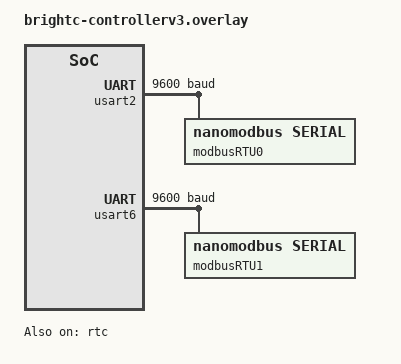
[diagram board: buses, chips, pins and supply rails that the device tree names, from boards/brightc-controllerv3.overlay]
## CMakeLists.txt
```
#-------------------------------------------------------------------------------
# Zephyr Example Application
#
# Copyright (c) 2021 Nordic Semiconductor ASA
# SPDX-License-Identifier: Apache-2.0

cmake_minimum_required(VERSION 3.13.1)
find_package(Zephyr REQUIRED HINTS $ENV{ZEPHYR_BASE})

project(app LANGUAGES C)

target_sources(app PRIVATE
    src/main.c
    src/application/active_objects/ao_modbus.c
    src/application/active_objects/ao_network.c
    src/application/active_objects/ao_sensor_matrix.c
    src/application/zbus/network_channels.c
    src/application/modbus/modbus_registry.c
    src/application/modbus/modbus_device_table.c
    src/domain/services/cwt_tm16pt_codec.c
    src/domain/services/jsy_mk339_codec.c
    src/domain/services/mbsl32di_codec.c
    src/domain/services/sensor_matrix_mapper.c
    src/domain/services/thermodynamic_engine.c
    src/domain/services/slave_scheduler.c
    src/domain/services/waveshare_relay_codec.c
    src/application/active_objects/ao_storage.c
    src/application/active_objects/ao_system_indicator.c
    src/application/active_objects/ao_digital_input.c
    src/application/zbus/config_channels.c
    src/application/zbus/indicator_channels.c
    src/application/zbus/digital_input_channels.c
    src/domain/services/digital_input_aggregator.c
    src/infrastructure/adapters/adapter_led_gpio.c
    src/infrastructure/adapters/adapter_buzzer_pwm.c
    src/infrastructure/adapters/adapter_di_gpio.c
    src/infrastructure/adapters/adapter_relay_gpio.c
    src/infrastructure/adapters/adapter_sensor_zephyr.c
    src/infrastructure/di/composition_root.c
    src/domain/models/hvac_unit_entity.c
    src/domain/models/hvac_group_entity.c
    src/application/zbus/hvac_channels.c
    src/application/zbus/sensor_channels.c
    src/infrastructure/adapters/adapter_hvac_actuator.c
    src/application/active_objects/ao_hvac.c
    src/application/services/app_facade.c
    src/domain/alarm/alarm_entity.c
    src/domain/alarm/alarm_aggregate.c
    src/domain/alarm/alarm_evaluator.c
    src/domain/alarm/alarm_registry.c
    src/application/zbus/alarm_channels.c
    src/application/active_objects/ao_alarm_manager.c
    src/infrastructure/adapters/adapter_alarm_detector_di.c
    src/infrastructure/adapters/adapter_alarm_detector_temp.c
    src/infrastructure/adapters/adapter_alarm_detector_volt.c
    src/infrastructure/adapters/adapter_alarm_detector_hvac.c
    src/domain/thermal_energy/humidity_transducer.c
    src/domain/thermal_energy/psychrometrics.c
    src/domain/thermal_energy/thermodynamics.c
    src/domain/thermal_energy/compressor_fsm.c
    src/domain/thermal_energy/predictive_analytics.c
    src/infrastructure/adapters/sensor_matrix_mapper.c
    src/application/zbus/thermal_channels.c
    src/application/active_objects/ao_thermal_energy.c
    src/domain/time/rtc_time_calc.c
    src/infrastructure/adapters/adapter_rtc_zephyr.c
    src/domain/storage/sd_lifecycle_sm.c
    src/application/zbus/storage_channels.c
    src/application/active_objects/ao_storage_sd.c
    src/infrastructure/adapters/adapter_storage_sd_zephyr.c
    src/infrastructure/adapters/adapter_modbus_tcp_server.c
    src/application/active_objects/ao_modbus_tcp.c
    src/domain/storage/bkpsram_ring.c
    src/infrastructure/adapters/adapter_bkpsram_stm32.c
    src/application/active_objects/ao_datalogger.c
    src/application/zbus/system_channels.c
)

if(CONFIG_SHELL)
    target_sources(app PRIVATE
        src/presentation/shell/shell_brightc.c
    )
endif()

if(CONFIG_MICROCONF)
    target_sources(app PRIVATE
        src/infrastructure/adapters/adapter_storage_microconf.c
    )
endif()

if(CONFIG_NETWORKING)
    target_sources(app PRIVATE
        src/infrastructure/adapters/adapter_eth_stm32.c
        src/infrastructure/adapters/adapter_wifi_esp_hosted.c
    )
endif()

target_include_directories(app PRIVATE
    include
    src
    lib
    # Public API of the out-of-tree ADC DMA engine. The header is always on the
    # include path so the composition root can reference the port-agnostic
    # adapter type even on platforms where the driver is not built.
    ${CMAKE_CURRENT_SOURCE_DIR}/../drivers/adc_dma/include
)

# The nanoMODBUS transport adapter is the only part that depends on the stack,
# so it is only compiled when the stack is enabled.
if(CONFIG_NANOMODBUS)
    target_sources(app PRIVATE
        src/infrastructure/adapters/adapter_modbus_nmbs.c
        src/infrastructure/adapters/adapter_relay_modbus.c
    )
endif()

# Bring-up diagnostic for a silent Modbus slave. Off unless the build asks for
# it, so a normal image carries no probe code at all.
if(CONFIG_APP_MODBUS_BUS_PROBE)
    target_sources(app PRIVATE src/application/diagnostics/modbus_bus_probe.c)
endif()

# The code below locates the git index file for this repository and adds it as a dependency for
# the application VERSION file so that if the repo has a new commit added, even if no files in
# the build have changed, the application version file will be regenerated with the new git commit
find_package(Git QUIET)
if(GIT_FOUND)
  execute_process(
    COMMAND ${GIT_EXECUTABLE} rev-parse --absolute-git-dir
    WORKING_DIRECTORY .
    OUTPUT_VARIABLE application_git_dir
    OUTPUT_STRIP_TRAILING_WHITESPACE
    ERROR_STRIP_TRAILING_WHITESPACE
    ERROR_VARIABLE stderr
    RESULT_VARIABLE return_code
  )
  # If there is an error e.g. it is not a git repo, we just silently ignore it and continue
  # without a dependency, this will be the case with freestanding applications.
  if(NOT return_code)
    if(NOT "${stderr}" STREQUAL "")
      message(WARNING "Application build version git rev-parse warned: ${stderr}")
    endif()

    set_property(TARGET app_version_h PROPERTY APP_VERSION_DEPENDS ${application_git_dir}/index)
  endif()
endif()
```

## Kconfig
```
# Copyright (c) 2021 Nordic Semiconductor ASA
# SPDX-License-Identifier: Apache-2.0
#
# This file is the application Kconfig entry point. All application Kconfig
# options can be defined here or included via other application Kconfig files.
# You can browse these options using the west targets menuconfig (terminal) or
# guiconfig (GUI).

menu "Zephyr"
source "Kconfig.zephyr"
endmenu

module = APP
module-str = APP
source "subsys/logging/Kconfig.template.log_config"

config APP_MODBUS_BUS_PROBE
	bool "Modbus bring-up diagnostic"
	depends on NANOMODBUS
	default n
	help
	  Sweep the Modbus slave addresses and the energy-meter register window
	  once at boot, before the polling threads claim the bus, and log every
	  outcome. It separates an addressing problem from a register-map one on
	  a slave that answers nothing. Diagnostic builds only: it costs one
	  transaction per probe and delays startup.

config APP_MODBUS_INTER_POLL_DELAY_MS
	int "Inter-poll turnaround delay in milliseconds"
	default 40
	range 0 1000
	help
	  Turnaround delay between consecutive Modbus transactions on the same
	  RS-485 bus. Gives slave transceivers time to release the bus and
	  satisfies the Modbus RTU inter-frame silence interval (t3.5+).

menu "BrightC Network Configuration"

config BRIGHTC_WIFI_DEFAULT_SSID
	string "Default Wi-Fi Soft-AP SSID"
	default "BrightC-AP"
	help
	  Default SSID broadcasted by the soft-AP interface.

config BRIGHTC_WIFI_DEFAULT_PSK
	string "Default Wi-Fi Soft-AP Pre-Shared Key (PSK)"
	default "12345678"
	help
	  Default WPA2 pre-shared key for the soft-AP interface.

config BRIGHTC_WIFI_DEFAULT_IP
	hex "Default Wi-Fi Soft-AP IPv4 Address"
	default 0xC0A80401
	help
	  Default IPv4 address of the soft-AP (0xC0A80401 = 192.168.4.1).

endmenu

rsource "Kconfig.modbus"

menu "BrightC Alarm Management Subsystem"

config ALARM_MANAGER_MAX_ALARMS
	int "Maximum tracked alarms in catalog"
	default 80
	range 32 256
	help
	  Maximum number of discrete and aggregated alarm descriptors and live
	  entities supported by the central alarm manager.

config AO_ALARM_MANAGER_QUEUE_DEPTH
	int "Active Object message queue depth"
	default 64
	range 16 256
	help
	  Capacity of the asynchronous condition event queue for ao_alarm_manager.

config AO_ALARM_MANAGER_STACK_SIZE
	int "Alarm Manager thread stack size"
	default 2048
	range 1024 8192
	help
	  Stack storage size allocated for the ao_alarm_manager thread.

endmenu

menu "BrightC Thermal and Energy Subsystem"

config THERMAL_HOURLY_PAIRS_COUNT
	int "Configured supply/return thermal pairs in hourly log"
	default 6
	range 1 16
	help
	  Number of supply/return temperature probe pairs stored per hourly
	  compressed record in datalogger storage.

config THERMAL_HOURLY_ROOM_PROBES_COUNT
	int "Configured room ambient probes in hourly log"
	default 2
	range 1 16
	help
	  Number of room ambient temperature probes stored per hourly
	  compressed record in datalogger storage.

config THERMAL_HOURLY_OUTDOOR_PROBES_COUNT
	int "Configured outdoor reference probes in hourly log"
	default 2
	range 1 8
	help
	  Number of outdoor ambient condenser reference probes stored per hourly
	  compressed record in datalogger storage.

endmenu

menu "BrightC Historical Datalogger & Event Logging Subsystem"

config DATALOGGER_BUFFER_SIZE
	int "Datalogger sector staging buffer size in bytes"
	default 512
	range 256 4096
	help
	  Size of sector-aligned RAM staging buffer allocated per active stream.

config DATALOGGER_FLUSH_INTERVAL_MS
	int "Datalogger inactivity hold-off flush timeout in milliseconds"
	default 5000
	range 1000 60000
	help
	  Duration of inactivity before staging buffers are automatically flushed.

endmenu
```

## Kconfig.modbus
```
# Copyright (c) 2026 DAECGE
# SPDX-License-Identifier: Apache-2.0
#
# BrightC Modbus topology - compile-time configuration (single source of truth).
#
# This fragment is sourced by app/Kconfig for production builds and by
# tests/unit/modbus/Kconfig for the unit-test build, so both compile exactly the
# same slave topology. The topology is static: it is fixed at build time and is
# never loaded from EEPROM nor edited at runtime.

menu "BrightC Modbus Configuration"

# --- 1. JSY-MK-339 3-phase AC energy meter (RS485-1) ---
menuconfig BRIGHTC_MODBUS_ENABLE_JSY_MK339
	bool "JSY-MK-339 3-Phase AC Energy Meter"
	default y
	help
	  Enable Modbus RTU polling for JSY-MK-339 3-Phase AC energy meter on RS485-1.

config BRIGHTC_MODBUS_ADDR_JSY_MK339
	int "Modbus slave address for JSY-MK-339"
	default 2
	range 1 247
	help
	  RTU slave address (1..247). Also used as the device identifier in the
	  compiled topology table.

# --- 2. CWT-TM-16PT 16-channel PT100 concentrator #1 (RS485-1) ---
menuconfig BRIGHTC_MODBUS_ENABLE_CWT_TM16PT_1
	bool "CWT-TM-16PT 16-channel PT100 Concentrator 1"
	default y
	help
	  Enable Modbus RTU polling for primary 16-channel PT100 concentrator on RS485-1.

config BRIGHTC_MODBUS_ADDR_CWT_TM16PT_1
	int "Modbus slave address for CWT-TM-16PT #1"
	default 1
	range 1 247
	help
	  RTU slave address (1..247). Also used as the device identifier in the
	  compiled topology table.

# --- 3. CWT-TM-16PT 16-channel PT100 concentrator #2 (RS485-1) ---
menuconfig BRIGHTC_MODBUS_ENABLE_CWT_TM16PT_2
	bool "CWT-TM-16PT 16-channel PT100 Concentrator 2"
	default n
	help
	  Enable Modbus RTU polling for secondary 16-channel PT100 concentrator on RS485-1.

config BRIGHTC_MODBUS_ADDR_CWT_TM16PT_2
	int "Modbus slave address for CWT-TM-16PT #2"
	default 5
	range 1 247
	help
	  RTU slave address (1..247). Also used as the device identifier in the
	  compiled topology table.

	  Every BRIGHTC_MODBUS_ADDR_* value must be unique across the whole plant,
	  not just within one bus: the registry keys devices by address, so two
	  devices sharing one would alias each other.

# --- 4. MBSL32DI 32-channel digital input module (RS485-2) ---
menuconfig BRIGHTC_MODBUS_ENABLE_MBSL32DI
	bool "MBSL32DI 32-channel Digital Input Expander"
	default y
	help
	  Enable Modbus RTU polling for 32-channel digital input module on RS485-2.

config BRIGHTC_MODBUS_ADDR_MBSL32DI
	int "Modbus slave address for MBSL32DI"
	default 3
	range 1 247
	help
	  RTU slave address (1..247). Also used as the device identifier of the
	  remote digital-input channels in hardware_pin_map.h.

# --- 5. Waveshare 32-channel relay expander (RS485-2) ---
menuconfig BRIGHTC_MODBUS_ENABLE_WAVESHARE_RELAY
	bool "Waveshare 32-channel Modbus Relay Expander"
	default y
	help
	  Enable Modbus RTU control for Waveshare 32-channel relay module on RS485-2.

config BRIGHTC_MODBUS_ADDR_WAVESHARE_RELAY
	int "Modbus slave address for Waveshare Relay"
	default 4
	range 1 247
	help
	  RTU slave address (1..247). Also used as the device identifier in the
	  compiled topology table.

endmenu
```

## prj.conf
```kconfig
# Copyright (c) 2021 Nordic Semiconductor ASA
# SPDX-License-Identifier: Apache-2.0
#
# This file contains selected Kconfig options for the application.

CONFIG_MAIN_STACK_SIZE=4096
CONFIG_SYSTEM_WORKQUEUE_STACK_SIZE=4096
CONFIG_HEAP_MEM_POOL_SIZE=32768
CONFIG_COMMON_LIBC_MALLOC_ARENA_SIZE=16384

# --- nanoMODBUS ---
CONFIG_NANOMODBUS=y
CONFIG_NANOMODBUS_CLIENT=y
CONFIG_NANOMODBUS_TRANSPORT_SERIAL=y
CONFIG_APP_MODBUS_INTER_POLL_DELAY_MS=40

# --- nanoMODBUS TCP Server ---
CONFIG_NANOMODBUS_SERVER=y
CONFIG_NANOMODBUS_TRANSPORT_TCP=y
CONFIG_NANOMODBUS_SERVER_TCP=y
CONFIG_NANOMODBUS_SERVER_TCP_STACK_SIZE=6144
CONFIG_NANOMODBUS_SERVER_TCP_PRIORITY=8
CONFIG_NANOMODBUS_SERVER_TCP_BACKLOG=4
CONFIG_NANOMODBUS_DIAGNOSTICS=y

# --- Logging (used by the composition root and the polling threads) ---
CONFIG_LOG=y
CONFIG_LOG_MODE_DEFERRED=y

# --- Thread Naming & Debugging ---
CONFIG_THREAD_NAME=y
CONFIG_DEBUG_THREAD_INFO=y

# --- Zbus ---
CONFIG_ZBUS=y

CONFIG_MAIN_STACK_SIZE=4096

# --- Networking Core & IPv4 ---
CONFIG_NETWORKING=y
CONFIG_NET_L2_ETHERNET=y
CONFIG_ETH_DRIVER=y
CONFIG_ETH_STM32_HAL=y
CONFIG_NET_IPV4=y
CONFIG_NET_DHCPV4=y
CONFIG_NET_MGMT=y
CONFIG_NET_MGMT_EVENT=y
CONFIG_NET_SOCKETS=y
CONFIG_NET_IF_MAX_IPV4_COUNT=3

# --- Network Buffer and Stacks ---
CONFIG_NET_RX_STACK_SIZE=4096
CONFIG_NET_TX_STACK_SIZE=4096
CONFIG_NET_MGMT_EVENT_STACK_SIZE=2048
CONFIG_NET_PKT_RX_COUNT=16
CONFIG_NET_PKT_TX_COUNT=16
CONFIG_NET_BUF_RX_COUNT=32
CONFIG_NET_BUF_TX_COUNT=32

# --- Wi-Fi Subsystem (ESP-Hosted-MCU) ---
CONFIG_WIFI=y
CONFIG_WIFI_ESP_HOSTED_MCU=y
CONFIG_ESP_HOSTED_MCU_INIT_PRIORITY=75
CONFIG_WIFI_ESP_HOSTED_MCU_AP_STA_MODE=y
CONFIG_ESP_HOSTED_MCU_EVENT_TASK_PRIORITY=-2
CONFIG_WIFI_NM_MAX_MANAGED_INTERFACES=2

# --- Native Zephyr WiFi/Net shell (diagnostics) ---
CONFIG_NET_L2_WIFI_SHELL=y
CONFIG_NET_SHELL=y

# --- DHCPv4 Server (Soft-AP Client IP Allocation) ---
CONFIG_NET_UDP=y
CONFIG_NET_TCP=y
CONFIG_NET_MAX_CONN=8
CONFIG_NET_MAX_CONTEXTS=16
CONFIG_ZVFS_POLL_MAX=8
CONFIG_NET_DHCPV4_SERVER=y
CONFIG_NET_DHCPV4_SERVER_INSTANCES=1
CONFIG_NET_DHCPV4_SERVER_ADDR_COUNT=8
CONFIG_NET_DHCPV4_SERVER_ADDR_LEASE_TIME=86400
CONFIG_NET_DHCPV4_SERVER_OPTION_ROUTER=y
CONFIG_NET_DHCPV4_SERVER_ICMP_PROBE_TIMEOUT=0
CONFIG_NET_DHCPV4_SERVER_NAK_UNRECOGNIZED_REQUESTS=y

# -----------------------------------------------------------------------------
# Peripherals & System
# -----------------------------------------------------------------------------
CONFIG_DCACHE=y
CONFIG_GPIO=y
CONFIG_PWM=y
CONFIG_DMA=y
CONFIG_SPI=y
CONFIG_SPI_STM32_INTERRUPT=y
CONFIG_UART_ASYNC_API=y
CONFIG_ADC_STM32_DMA=y

# --- UART RX ---
CONFIG_SERIAL=y
CONFIG_UART_INTERRUPT_DRIVEN=y
CONFIG_UART_USE_RUNTIME_CONFIGURE=y

# --- I2C & EEPROM Subsystems ---
CONFIG_I2C=y
CONFIG_EEPROM=y
CONFIG_EEPROM_AT24=y

# --- microconf Persistent Storage Engine ---
CONFIG_MICROCONF=y
CONFIG_MICROCONF_BACKEND_EEPROM=y

# --- Real-Time Clock (RTC) Subsystem ---
CONFIG_RTC=y
CONFIG_RTC_STM32=y

# --- Zephyr Shell Subsystem ---
CONFIG_SHELL=y
CONFIG_SHELL_STACK_SIZE=6144
CONFIG_SHELL_BACKENDS=y
CONFIG_SHELL_BACKEND_SERIAL=y
CONFIG_SHELL_PROMPT_UART="brightc:~$ "
CONFIG_SHELL_CMD_BUFF_SIZE=256
CONFIG_SHELL_PRINTF_BUFF_SIZE=512

# --- System Reboot ---
CONFIG_REBOOT=y

CONFIG_PICOLIBC_IO_FLOAT=y

# --- Hardware FPU (Cortex-M7 FPv5-D16 Double Precision) ---
CONFIG_FPU=y
CONFIG_FPU_SHARING=y

# --- ARM CMSIS-DSP Library Support ---
CONFIG_CMSIS_DSP=y

# --- MicroSD Storage & FAT Filesystem ---
CONFIG_DISK_ACCESS=y
CONFIG_DISK_DRIVER_SDMMC=y
CONFIG_FILE_SYSTEM=y
CONFIG_FAT_FILESYSTEM_ELM=y
CONFIG_FS_FATFS_LFN=y
CONFIG_FS_FATFS_LFN_MODE_STACK=y
CONFIG_FS_FATFS_MAX_LFN=64
CONFIG_FS_FATFS_REENTRANT=y
```

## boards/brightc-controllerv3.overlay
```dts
/ {
	aliases {
		modbus-uart-1 = &usart2;
		modbus-uart-2 = &usart6;
		modbus-rtu-1 = &modbusRTU0;
		modbus-rtu-2 = &modbusRTU1;
		rtc = &rtc;
	};
};

&rtc {
	clocks = <&rcc STM32_CLOCK(APB4, 16)>,
		 <&rcc STM32_SRC_LSE RTC_SEL(1)>;
	async-prescaler = <127>;
	sync-prescaler = <255>;
	status = "okay";
};

&usart2 {
	/*default baud rate */
	current-speed = <9600>;
	/*default de-assert time */
	de-assert-time = <1>;
	/*default de-deassert time */
	de-deassert-time = <16>;

	/*nanomodbus*/
	modbusRTU0: modbusRTU0 {
		compatible = "nanomodbus,serial";
		status = "okay";
		de-mode = "hardware";
		rx-mode = "irq";
	};
};

&usart6 {
	/*default baud rate */
	current-speed = <9600>;
	/*default de-assert time */
	de-assert-time = <1>;
	/*default de-deassert time */
	de-deassert-time = <16>;

	/*nanomodbus*/
	modbusRTU1: modbusRTU1 {
		compatible = "nanomodbus,serial";
		status = "okay";
		de-mode = "hardware";
		rx-mode = "irq";
	};
};
```

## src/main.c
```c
/*
 * Copyright (c) 2026 DAECGE
 * SPDX-License-Identifier: Apache-2.0
 *
 * Application entry point. The only mutable static object of the firmware is
 * the container below; every other component receives it by reference from the
 * composition root.
 */

#include <zephyr/drivers/gpio.h>
#include <zephyr/kernel.h>
#include <zephyr/logging/log.h>

#if defined(CONFIG_APP_MODBUS_BUS_PROBE)
#include "application/diagnostics/modbus_bus_probe.h"
#endif

#include "application/services/app_facade.h"
#include "infrastructure/di/composition_root.h"

LOG_MODULE_REGISTER(main, CONFIG_APP_LOG_LEVEL);

/* Keep boot messages easy to scan when several modules are logging together. */
#define BOOT_INF(fmt, ...) LOG_INF("[BOOT] " fmt, ##__VA_ARGS__)
#define BOOT_WRN(fmt, ...) LOG_WRN("[BOOT] " fmt, ##__VA_ARGS__)
#define BOOT_ERR(fmt, ...) LOG_ERR("[BOOT] " fmt, ##__VA_ARGS__)

static app_container_t g_app;

#if DT_NODE_EXISTS(DT_ALIAS(sw0))
static const struct gpio_dt_spec s_user_button = GPIO_DT_SPEC_GET(DT_ALIAS(sw0), gpios);
#endif

static void check_boot_factory_reset(app_container_t *app)
{
#if DT_NODE_EXISTS(DT_ALIAS(sw0))
	if (!gpio_is_ready_dt(&s_user_button)) {
		return;
	}

	if (gpio_pin_configure_dt(&s_user_button, GPIO_INPUT) != 0) {
		return;
	}

	if (gpio_pin_get_dt(&s_user_button) > 0) {
		BOOT_INF("factory-reset input asserted; sampling for 5 s");
		int held_ms = 0;
		while (held_ms < 5000 && gpio_pin_get_dt(&s_user_button) > 0) {
			k_sleep(K_MSEC(100));
			held_ms += 100;
		}

		if (held_ms >= 5000) {
			BOOT_WRN("factory-reset hold confirmed; restoring persistent defaults");
			(void)app_facade_storage_reset_defaults();

			const i_led_t *led = app_container_get_led(app);
			if (led != NULL) {
				for (int i = 0; i < 5; i++) {
					(void)i_led_set_state(led, true);
					k_sleep(K_MSEC(100));
					(void)i_led_set_state(led, false);
					k_sleep(K_MSEC(100));
				}
			}
		} else {
			BOOT_INF("factory-reset hold cancelled after %d ms; continuing normal boot", held_ms);
		}
	}
#else
	ARG_UNUSED(app);
#endif
}

int main(void)
{
	BOOT_INF("BrightC telemetry controller boot sequence started");
	BOOT_INF("initializing dependency-injection container and hardware adapters");
	int err = composition_root_init(&g_app);

	if (err != 0)
	{
		BOOT_ERR("composition-root initialization failed: rc=%d", err);
		return err;
	}
	BOOT_INF("composition-root initialization complete; all required dependencies wired");

	err = app_facade_init(&g_app);
	if (err != 0) {
		BOOT_ERR("application facade initialization failed: rc=%d", err);
		return err;
	}
	BOOT_INF("application facade initialized");

	check_boot_factory_reset(&g_app);

#if defined(CONFIG_APP_MODBUS_BUS_PROBE)
	/* Must run before composition_root_start(): the polling threads of this
	 * bus would interleave their frames with the probe's. */
	const i_modbus_client_t *probe_client =
		app_container_get_modbus_client(&g_app, (uint8_t)MODBUS_BUS_RS485_1);

	if (probe_client != NULL && i_modbus_client_is_bound(probe_client))
	{
		modbus_bus_probe_run(probe_client, (uint8_t)MODBUS_BUS_RS485_1);
	}
#endif

	err = composition_root_start(&g_app);
	if (err != 0)
	{
		BOOT_ERR("composition-root start failed: rc=%d", err);
		return err;
	}

	BOOT_INF("runtime started successfully; controller is operational");

	while (true)
	{
		k_sleep(K_MSEC(1000U));
	}
	return 0;
}
```
